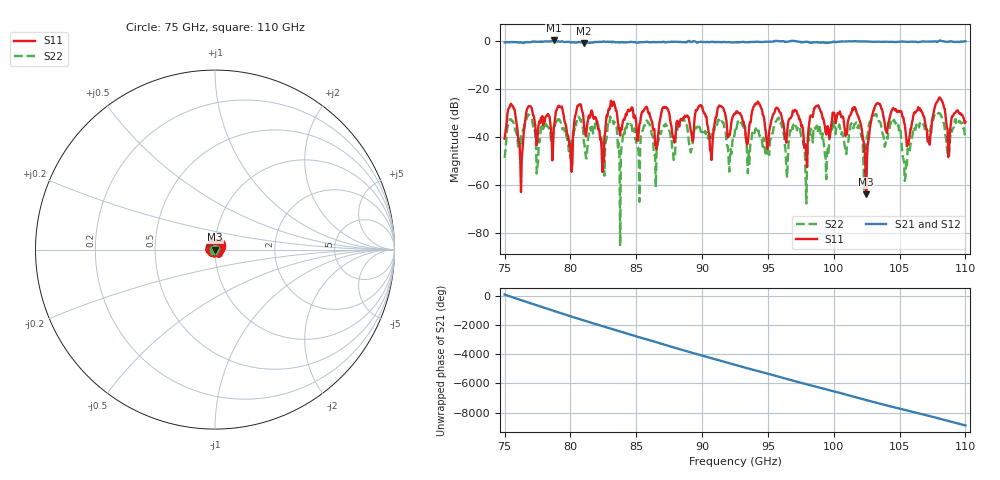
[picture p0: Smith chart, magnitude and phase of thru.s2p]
!Created with skrf (http://scikit-rf.org).
# GHz S RI R 50.0
!freq ReS11 ImS11 ReS21 ImS21 ReS12 ImS12 ReS22 ImS22
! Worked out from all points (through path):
!   647 points, 75 GHz to 110 GHz, reference 50 ohm
!   highest |S21| = 0.22 dB at 78.74 GHz (marker M1); lowest = -0.8 dB at 81.02 GHz (marker M2)
!   lowest |S11| = -63.8 dB at 102.5 GHz (marker M3), VSWR 1.00, Z = 50.1 - j0.0275 ohm
!   |S11| at or under -10 dB: start of sweep to end of sweep
!   |S22| runs from -85.5 to -29.7 dB; largest |S21 - S12| = 0.019
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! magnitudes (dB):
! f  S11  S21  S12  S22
! 75 GHz  -40.7  -0.6  -0.6  -48.7
! 75.49 GHz  -26.2  -0.5  -0.4  -32.7
! 76.2 GHz  -50.2  -0.6  -0.6  -44.2
! 76.85 GHz  -27.1  -0.5  -0.5  -30.9
! 78.74 GHz  -36.3  0.2  0.2  -35.7
! 79.23 GHz  -27.6  -0.3  -0.3  -33.6
! 80.04 GHz  -50.4  -0.6  -0.6  -48.2
! 80.85 GHz  -28.3  -0.6  -0.6  -34.6
! 81.02 GHz  -33.9  -0.8  -0.8  -42.0
! 86.7 GHz  -37.3  -0.4  -0.5  -41.4
! 92.5 GHz  -30.4  -0.6  -0.5  -37.5
! 97.27 GHz  -30.8  -0.3  -0.3  -35.5
! 97.86 GHz  -43.8  -0.3  -0.3  -56.7
! 98.35 GHz  -31.1  -0.6  -0.6  -38.7
! 101.6 GHz  -27.6  -0.1  -0.1  -34.6
! 102.5 GHz  -63.8  -0.2  -0.2  -42.7
! 103.2 GHz  -26.8  -0.3  -0.3  -31.0
! 104.2 GHz  -33.0  -0.4  -0.4  -37.2
! 105.4 GHz  -34.8  -0.3  -0.3  -58.3
! 107.2 GHz  -41.9  -0.2  -0.2  -40.0
! 107.8 GHz  -25.4  -0.4  -0.4  -29.7
! 110 GHz  -33.8  -0.1  -0.1  -40.1
